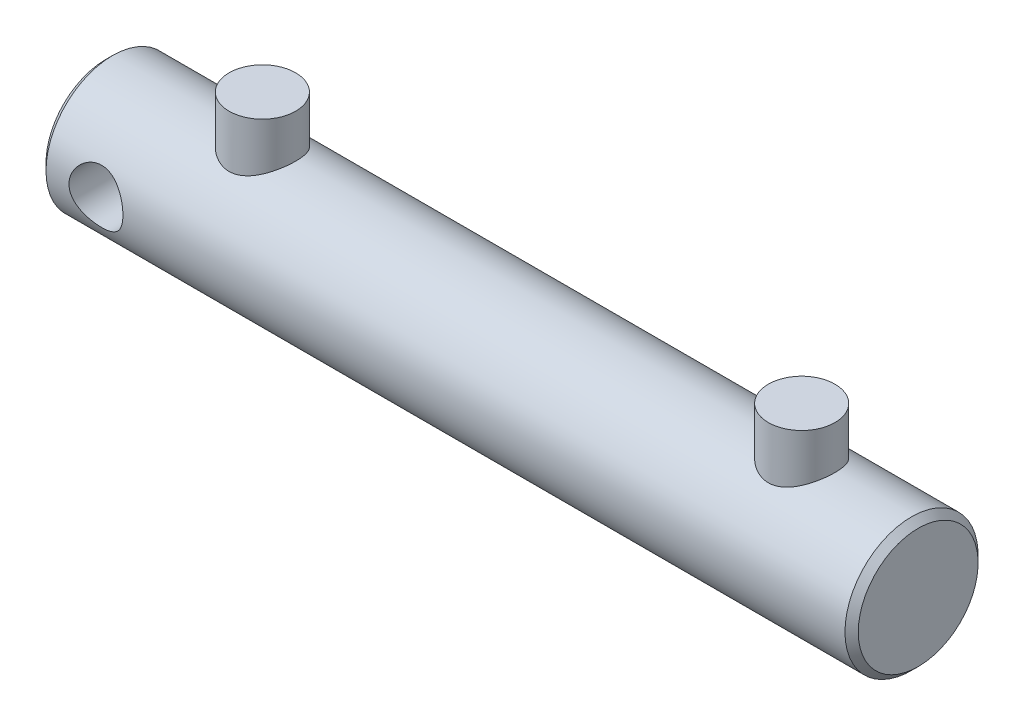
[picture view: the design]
ISO-10303-21;
HEADER;
FILE_DESCRIPTION(('STEP AP214'),'2;1');
FILE_NAME('part.step','',(''),(''),'','','');
FILE_SCHEMA(('AUTOMOTIVE_DESIGN { 1 0 10303 214 1 1 1 1 }'));
ENDSEC;
DATA;
#1=APPLICATION_CONTEXT('core data for automotive mechanical design processes');
#2=APPLICATION_PROTOCOL_DEFINITION('international standard','automotive_design',2000,#1);
#3=PRODUCT_CONTEXT('',#1,'mechanical');
#4=PRODUCT('Part','Part','',(#3));
#5=PRODUCT_RELATED_PRODUCT_CATEGORY('part','',(#4));
#6=PRODUCT_DEFINITION_FORMATION('','',#4);
#7=PRODUCT_DEFINITION_CONTEXT('part definition',#1,'design');
#8=PRODUCT_DEFINITION('design','',#6,#7);
#9=PRODUCT_DEFINITION_SHAPE('','',#8);
#10=(LENGTH_UNIT() NAMED_UNIT(*) SI_UNIT(.MILLI.,.METRE.));
#11=(NAMED_UNIT(*) PLANE_ANGLE_UNIT() SI_UNIT($,.RADIAN.));
#12=(NAMED_UNIT(*) SI_UNIT($,.STERADIAN.) SOLID_ANGLE_UNIT());
#13=UNCERTAINTY_MEASURE_WITH_UNIT(LENGTH_MEASURE(1.E-05),#10,'distance_accuracy_value','');
#14=(GEOMETRIC_REPRESENTATION_CONTEXT(3) GLOBAL_UNCERTAINTY_ASSIGNED_CONTEXT((#13)) GLOBAL_UNIT_ASSIGNED_CONTEXT((#10,
#11,#12)) REPRESENTATION_CONTEXT('',''));
#15=CARTESIAN_POINT('',(0.,0.,0.));
#16=DIRECTION('',(0.,0.,1.));
#17=DIRECTION('',(1.,0.,0.));
#18=AXIS2_PLACEMENT_3D('',#15,#16,#17);
#19=CARTESIAN_POINT('',(-122.,0.,0.));
#20=DIRECTION('',(-1.,0.,0.));
#21=DIRECTION('',(0.,0.,1.));
#22=AXIS2_PLACEMENT_3D('',#19,#20,#21);
#23=CYLINDRICAL_SURFACE('',#22,20.);
#24=CARTESIAN_POINT('',(-75.0000000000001,17.3205080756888,-10.));
#25=CARTESIAN_POINT('',(-75.2606630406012,17.3205095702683,-9.99999887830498));
#26=CARTESIAN_POINT('',(-75.5213487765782,17.3264124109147,-9.98979463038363));
#27=CARTESIAN_POINT('',(-76.0407114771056,17.3498046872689,-9.94911125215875));
#28=CARTESIAN_POINT('',(-76.2993874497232,17.3672995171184,-9.91862268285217));
#29=CARTESIAN_POINT('',(-76.8130233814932,17.4132568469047,-9.83771551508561));
#30=CARTESIAN_POINT('',(-77.0679768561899,17.4417365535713,-9.78726564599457));
#31=CARTESIAN_POINT('',(-77.5720498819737,17.5086546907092,-9.66704369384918));
#32=CARTESIAN_POINT('',(-77.821166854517,17.5470974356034,-9.59726323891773));
#33=CARTESIAN_POINT('',(-78.3104736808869,17.6323996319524,-9.43962165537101));
#34=CARTESIAN_POINT('',(-78.5507068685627,17.6792090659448,-9.35186754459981));
#35=CARTESIAN_POINT('',(-79.0225542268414,17.779982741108,-9.15882440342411));
#36=CARTESIAN_POINT('',(-79.2541652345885,17.8339495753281,-9.05352901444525));
#37=CARTESIAN_POINT('',(-79.7075453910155,17.9475017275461,-8.82628481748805));
#38=CARTESIAN_POINT('',(-79.9293168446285,18.007085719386,-8.70433993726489));
#39=CARTESIAN_POINT('',(-80.3621596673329,18.1303531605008,-8.4445816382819));
#40=CARTESIAN_POINT('',(-80.573230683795,18.1940367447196,-8.30676769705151));
#41=CARTESIAN_POINT('',(-81.000837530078,18.329363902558,-8.00400718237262));
#42=CARTESIAN_POINT('',(-81.216382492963,18.4012302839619,-7.83775940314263));
#43=CARTESIAN_POINT('',(-81.6329349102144,18.5460965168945,-7.48852658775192));
#44=CARTESIAN_POINT('',(-81.8339460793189,18.6190960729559,-7.30554585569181));
#45=CARTESIAN_POINT('',(-82.2206945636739,18.7644955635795,-6.92354675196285));
#46=CARTESIAN_POINT('',(-82.4064192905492,18.8368949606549,-6.72451542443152));
#47=CARTESIAN_POINT('',(-82.7613467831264,18.9792540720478,-6.3115450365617));
#48=CARTESIAN_POINT('',(-82.9305553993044,19.0492146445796,-6.09761130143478));
#49=CARTESIAN_POINT('',(-83.2623641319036,19.1896470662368,-5.64077435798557));
#50=CARTESIAN_POINT('',(-83.4237392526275,19.2598322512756,-5.39689043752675));
#51=CARTESIAN_POINT('',(-83.7252065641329,19.3935808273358,-4.89454568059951));
#52=CARTESIAN_POINT('',(-83.8652975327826,19.4571438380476,-4.63608400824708));
#53=CARTESIAN_POINT('',(-84.1227489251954,19.5757886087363,-4.10635184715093));
#54=CARTESIAN_POINT('',(-84.240120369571,19.6308744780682,-3.83508764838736));
#55=CARTESIAN_POINT('',(-84.4508629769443,19.7309453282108,-3.28159286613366));
#56=CARTESIAN_POINT('',(-84.5442366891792,19.775931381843,-2.99936345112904));
#57=CARTESIAN_POINT('',(-84.7000287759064,19.8516061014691,-2.44661617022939));
#58=CARTESIAN_POINT('',(-84.7641767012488,19.8830841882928,-2.17669338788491));
#59=CARTESIAN_POINT('',(-84.8699306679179,19.9352303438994,-1.6314331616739));
#60=CARTESIAN_POINT('',(-84.9115376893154,19.9558988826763,-1.35609595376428));
#61=CARTESIAN_POINT('',(-84.9716398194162,19.9858180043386,-0.802434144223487));
#62=CARTESIAN_POINT('',(-84.9901467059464,19.9950744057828,-0.52411113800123));
#63=CARTESIAN_POINT('',(-85.003828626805,20.001913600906,0.0332441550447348));
#64=CARTESIAN_POINT('',(-84.9990050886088,19.9994971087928,0.31227639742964));
#65=CARTESIAN_POINT('',(-84.9675360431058,19.9837839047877,0.844365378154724));
#66=CARTESIAN_POINT('',(-84.9428274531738,19.9714530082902,1.09756809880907));
#67=CARTESIAN_POINT('',(-84.8743173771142,19.9374335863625,1.60072224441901));
#68=CARTESIAN_POINT('',(-84.8305172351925,19.9157457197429,1.85067389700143));
#69=CARTESIAN_POINT('',(-84.7243003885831,19.8635314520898,2.34564683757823));
#70=CARTESIAN_POINT('',(-84.6618830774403,19.8330047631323,2.59066796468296));
#71=CARTESIAN_POINT('',(-84.5190690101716,19.7638249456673,3.0742307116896));
#72=CARTESIAN_POINT('',(-84.4386716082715,19.7251715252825,3.31277209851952));
#73=CARTESIAN_POINT('',(-84.2594279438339,19.6400278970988,3.78519130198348));
#74=CARTESIAN_POINT('',(-84.1603459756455,19.5934383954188,4.01896179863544));
#75=CARTESIAN_POINT('',(-83.9453098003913,19.4938328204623,4.47722728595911));
#76=CARTESIAN_POINT('',(-83.8293496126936,19.4408144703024,4.70171895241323));
#77=CARTESIAN_POINT('',(-83.4574852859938,19.2738101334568,5.35951935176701));
#78=CARTESIAN_POINT('',(-83.1774883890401,19.1518214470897,5.7774381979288));
#79=CARTESIAN_POINT('',(-82.5309599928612,18.8844067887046,6.60185513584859));
#80=CARTESIAN_POINT('',(-82.1587504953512,18.7378553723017,7.00353936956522));
#81=CARTESIAN_POINT('',(-81.5553615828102,18.5185765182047,7.55658054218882));
#82=CARTESIAN_POINT('',(-81.346548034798,18.4455210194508,7.73279224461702));
#83=CARTESIAN_POINT('',(-80.9146773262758,18.301419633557,8.06791510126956));
#84=CARTESIAN_POINT('',(-80.6916180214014,18.2303740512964,8.22682364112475));
#85=CARTESIAN_POINT('',(-80.2176662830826,18.0878347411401,8.53586780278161));
#86=CARTESIAN_POINT('',(-79.9659060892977,18.0166021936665,8.68479491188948));
#87=CARTESIAN_POINT('',(-79.448949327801,17.8810231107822,8.9606151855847));
#88=CARTESIAN_POINT('',(-79.1837588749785,17.8166734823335,9.08751826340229));
#89=CARTESIAN_POINT('',(-78.6415971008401,17.6972138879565,9.31801905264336));
#90=CARTESIAN_POINT('',(-78.3646328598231,17.6420984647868,9.42163054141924));
#91=CARTESIAN_POINT('',(-77.8007562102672,17.5432965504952,9.60435110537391));
#92=CARTESIAN_POINT('',(-77.5138451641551,17.4996085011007,9.68346352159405));
#93=CARTESIAN_POINT('',(-76.9554952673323,17.4285246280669,9.81078056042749));
#94=CARTESIAN_POINT('',(-76.6846306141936,17.400112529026,9.86093677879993));
#95=CARTESIAN_POINT('',(-76.1386742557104,17.355765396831,9.93878416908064));
#96=CARTESIAN_POINT('',(-75.8635827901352,17.3398296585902,9.96647661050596));
#97=CARTESIAN_POINT('',(-75.3117693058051,17.3211203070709,9.99895720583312));
#98=CARTESIAN_POINT('',(-75.035048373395,17.3183387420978,10.0037591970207));
#99=CARTESIAN_POINT('',(-74.4823571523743,17.3260388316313,9.99041751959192));
#100=CARTESIAN_POINT('',(-74.2063868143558,17.3365195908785,9.97227539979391));
#101=CARTESIAN_POINT('',(-73.6878300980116,17.3684286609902,9.91658048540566));
#102=CARTESIAN_POINT('',(-73.4449043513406,17.3885290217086,9.88137691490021));
#103=CARTESIAN_POINT('',(-72.9631581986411,17.4382137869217,9.79342893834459));
#104=CARTESIAN_POINT('',(-72.7243391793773,17.467801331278,9.74067872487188));
#105=CARTESIAN_POINT('',(-72.2523728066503,17.5355331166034,9.61821012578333));
#106=CARTESIAN_POINT('',(-72.0192247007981,17.5736762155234,9.54849400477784));
#107=CARTESIAN_POINT('',(-71.5597756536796,17.6574071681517,9.39275103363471));
#108=CARTESIAN_POINT('',(-71.3334774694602,17.7029979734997,9.30671771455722));
#109=CARTESIAN_POINT('',(-70.6461619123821,17.8535843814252,9.01657018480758));
#110=CARTESIAN_POINT('',(-70.1983271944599,17.9691397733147,8.78600743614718));
#111=CARTESIAN_POINT('',(-69.3451898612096,18.2156365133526,8.26280380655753));
#112=CARTESIAN_POINT('',(-68.93990925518,18.3465857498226,7.97013103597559));
#113=CARTESIAN_POINT('',(-68.3445899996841,18.5540860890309,7.46888401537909));
#114=CARTESIAN_POINT('',(-68.1378065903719,18.6294365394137,7.27935116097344));
#115=CARTESIAN_POINT('',(-67.7407576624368,18.7793184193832,6.8834540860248));
#116=CARTESIAN_POINT('',(-67.5504872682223,18.8538500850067,6.67709486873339));
#117=CARTESIAN_POINT('',(-67.1874055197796,19.0002370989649,6.24838707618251));
#118=CARTESIAN_POINT('',(-67.0146073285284,19.0720904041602,6.02602665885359));
#119=CARTESIAN_POINT('',(-66.687849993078,19.2111944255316,5.56664786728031));
#120=CARTESIAN_POINT('',(-66.533882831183,19.2784470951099,5.32963579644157));
#121=CARTESIAN_POINT('',(-66.2420643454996,19.4083463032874,4.83560208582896));
#122=CARTESIAN_POINT('',(-66.1047543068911,19.4708214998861,4.57821478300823));
#123=CARTESIAN_POINT('',(-65.8525290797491,19.5873354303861,4.05082787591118));
#124=CARTESIAN_POINT('',(-65.7376146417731,19.6413738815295,3.78082784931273));
#125=CARTESIAN_POINT('',(-65.5315676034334,19.7393769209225,3.23033940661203));
#126=CARTESIAN_POINT('',(-65.4404180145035,19.7833487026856,2.94985864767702));
#127=CARTESIAN_POINT('',(-65.2829809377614,19.8599022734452,2.38049331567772));
#128=CARTESIAN_POINT('',(-65.2166905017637,19.8924854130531,2.09160974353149));
#129=CARTESIAN_POINT('',(-65.1148104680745,19.942798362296,1.53480500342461));
#130=CARTESIAN_POINT('',(-65.0769613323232,19.9616170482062,1.26739371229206));
#131=CARTESIAN_POINT('',(-65.0230133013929,19.9884894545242,0.729851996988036));
#132=CARTESIAN_POINT('',(-65.0069130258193,19.9965438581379,0.459721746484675));
#133=CARTESIAN_POINT('',(-64.996673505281,20.0016629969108,-0.0809759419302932));
#134=CARTESIAN_POINT('',(-65.0025277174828,19.998731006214,-0.351543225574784));
#135=CARTESIAN_POINT('',(-65.0361056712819,19.9819662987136,-0.890971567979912));
#136=CARTESIAN_POINT('',(-65.0638288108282,19.9681338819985,-1.15983267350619));
#137=CARTESIAN_POINT('',(-65.1382400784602,19.9312153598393,-1.67605139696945));
#138=CARTESIAN_POINT('',(-65.18355535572,19.9088004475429,-1.9236568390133));
#139=CARTESIAN_POINT('',(-65.292457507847,19.8553300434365,-2.41384547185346));
#140=CARTESIAN_POINT('',(-65.3560433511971,19.8242750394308,-2.65642894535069));
#141=CARTESIAN_POINT('',(-65.5008477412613,19.7542370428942,-3.13506320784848));
#142=CARTESIAN_POINT('',(-65.5820646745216,19.7152547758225,-3.3711145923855));
#143=CARTESIAN_POINT('',(-65.7614308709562,19.6302044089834,-3.83546861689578));
#144=CARTESIAN_POINT('',(-65.8595866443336,19.5841335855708,-4.06376823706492));
#145=CARTESIAN_POINT('',(-66.0765183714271,19.483810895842,-4.52085803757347));
#146=CARTESIAN_POINT('',(-66.1959918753,19.4292950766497,-4.74925902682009));
#147=CARTESIAN_POINT('',(-66.4515659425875,19.3148302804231,-5.19522438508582));
#148=CARTESIAN_POINT('',(-66.587672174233,19.2548794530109,-5.4127850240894));
#149=CARTESIAN_POINT('',(-66.8755967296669,19.1308402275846,-5.83606045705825));
#150=CARTESIAN_POINT('',(-67.0274181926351,19.0667510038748,-6.0417728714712));
#151=CARTESIAN_POINT('',(-67.3458750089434,18.9358010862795,-6.44045588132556));
#152=CARTESIAN_POINT('',(-67.5125111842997,18.8689402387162,-6.63342576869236));
#153=CARTESIAN_POINT('',(-67.8770952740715,18.7271146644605,-7.02443076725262));
#154=CARTESIAN_POINT('',(-68.0765084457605,18.6520069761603,-7.22105023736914));
#155=CARTESIAN_POINT('',(-68.4911102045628,18.5021161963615,-7.59688252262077));
#156=CARTESIAN_POINT('',(-68.7062943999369,18.4273330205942,-7.77610015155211));
#157=CARTESIAN_POINT('',(-69.1516671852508,18.2800108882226,-8.1163793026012));
#158=CARTESIAN_POINT('',(-69.3818705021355,18.2074742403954,-8.27742256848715));
#159=CARTESIAN_POINT('',(-69.8560212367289,18.0668000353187,-8.58012843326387));
#160=CARTESIAN_POINT('',(-70.0999705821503,17.9986630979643,-8.72178830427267));
#161=CARTESIAN_POINT('',(-70.6083744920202,17.8668466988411,-8.98880823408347));
#162=CARTESIAN_POINT('',(-70.8732353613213,17.8033795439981,-9.11350193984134));
#163=CARTESIAN_POINT('',(-71.414528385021,17.6857538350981,-9.3397203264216));
#164=CARTESIAN_POINT('',(-71.6909544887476,17.6315904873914,-9.44125694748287));
#165=CARTESIAN_POINT('',(-72.2528111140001,17.5348420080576,-9.61975104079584));
#166=CARTESIAN_POINT('',(-72.5382163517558,17.4922271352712,-9.69677174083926));
#167=CARTESIAN_POINT('',(-73.1161855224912,17.420295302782,-9.82541504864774));
#168=CARTESIAN_POINT('',(-73.4087442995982,17.3909690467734,-9.8770554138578));
#169=CARTESIAN_POINT('',(-73.9179955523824,17.3529508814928,-9.94364603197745));
#170=CARTESIAN_POINT('',(-74.1336483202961,17.340814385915,-9.96475859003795));
#171=CARTESIAN_POINT('',(-74.5661954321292,17.3245920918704,-9.99293651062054));
#172=CARTESIAN_POINT('',(-74.7830898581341,17.3205068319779,-10.0000009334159));
#173=CARTESIAN_POINT('',(-75.0000000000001,17.3205080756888,-10.));
#174=B_SPLINE_CURVE_WITH_KNOTS('',3,(#24,#25,#26,#27,#28,#29,#30,#31,#32,#33,#34,#35,#36,#37,
#38,#39,#40,#41,#42,#43,#44,#45,#46,#47,#48,#49,#50,#51,#52,#53,#54,#55,#56,#57,#58,#59,#60,#61,
#62,#63,#64,#65,#66,#67,#68,#69,#70,#71,#72,#73,#74,#75,#76,#77,#78,#79,#80,#81,#82,#83,#84,#85,
#86,#87,#88,#89,#90,#91,#92,#93,#94,#95,#96,#97,#98,#99,#100,#101,#102,#103,#104,#105,#106,#107,
#108,#109,#110,#111,#112,#113,#114,#115,#116,#117,#118,#119,#120,#121,#122,#123,#124,#125,#126,
#127,#128,#129,#130,#131,#132,#133,#134,#135,#136,#137,#138,#139,#140,#141,#142,#143,#144,#145,
#146,#147,#148,#149,#150,#151,#152,#153,#154,#155,#156,#157,#158,#159,#160,#161,#162,#163,#164,
#165,#166,#167,#168,#169,#170,#171,#172,#173),.UNSPECIFIED.,.T.,.F.,(4,2,2,2,2,2,2,2,2,2,2,2,2,
2,2,2,2,2,2,2,2,2,2,2,2,2,2,2,2,2,2,2,2,2,2,2,2,2,2,2,2,2,2,2,2,2,2,2,2,2,2,2,2,2,2,2,2,2,2,2,2,
2,2,2,2,2,2,2,2,2,2,2,2,2,4),(0.,0.781764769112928,1.56389357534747,2.34725251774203,
3.13095125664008,3.91011273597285,4.68955727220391,5.46881824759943,6.24810488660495,
7.09181817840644,7.93531505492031,8.7794997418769,9.62338430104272,10.5244589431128,
11.4255853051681,12.3262734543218,13.2268658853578,14.0633930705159,14.8998838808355,
15.735948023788,16.571961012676,17.3351709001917,18.0983270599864,18.8615080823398,
19.6247165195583,20.3982891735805,21.1721366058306,22.7189130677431,24.4119022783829,
25.2596540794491,26.1075337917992,27.0095657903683,27.9111907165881,28.8122809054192,
29.7132481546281,30.5428616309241,31.3724282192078,32.2014932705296,33.0305023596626,
33.7685142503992,34.5067706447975,35.2449285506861,35.9833797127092,37.5272041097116,
39.0718230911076,39.9423348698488,40.8125887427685,41.6834934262,42.5540260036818,
43.4478458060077,44.3416955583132,45.2349045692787,46.1280076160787,46.9391312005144,
47.7502033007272,48.5610337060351,49.371841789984,50.1291222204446,50.8863599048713,
51.6435283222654,52.4009883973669,53.190547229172,53.980375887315,54.7703626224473,
55.5603932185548,56.4292490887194,57.297863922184,58.1673436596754,59.0369456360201,
59.934364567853,60.8313197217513,61.7259424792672,62.6199384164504,63.27043863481,
63.9209823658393),.UNSPECIFIED.);
#175=CARTESIAN_POINT('',(-75.0000000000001,17.3205080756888,-10.));
#176=VERTEX_POINT('',#175);
#177=EDGE_CURVE('E38',#176,#176,#174,.T.);
#178=ORIENTED_EDGE('',*,*,#177,.F.);
#179=EDGE_LOOP('',(#178));
#180=FACE_BOUND('',#179,.T.);
#181=CARTESIAN_POINT('',(-96.9,0.,-20.));
#182=CARTESIAN_POINT('',(-96.900001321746,0.217553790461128,-19.9999989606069));
#183=CARTESIAN_POINT('',(-96.9087767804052,0.435188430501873,-19.9964404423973));
#184=CARTESIAN_POINT('',(-96.9437988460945,0.868915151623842,-19.9822953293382));
#185=CARTESIAN_POINT('',(-96.9700569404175,1.08500612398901,-19.9717041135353));
#186=CARTESIAN_POINT('',(-97.0398578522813,1.51445060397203,-19.9437418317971));
#187=CARTESIAN_POINT('',(-97.0834401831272,1.72779669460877,-19.9263552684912));
#188=CARTESIAN_POINT('',(-97.1874521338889,2.14972461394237,-19.8852614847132));
#189=CARTESIAN_POINT('',(-97.2478829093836,2.35830611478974,-19.8615538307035));
#190=CARTESIAN_POINT('',(-97.3847842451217,2.76859175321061,-19.8085220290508));
#191=CARTESIAN_POINT('',(-97.4611994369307,2.97031690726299,-19.7792172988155));
#192=CARTESIAN_POINT('',(-97.6295344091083,3.36638434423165,-19.7156711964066));
#193=CARTESIAN_POINT('',(-97.7214547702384,3.56072635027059,-19.6814296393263));
#194=CARTESIAN_POINT('',(-97.9200165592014,3.94078379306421,-19.6088661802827));
#195=CARTESIAN_POINT('',(-98.0266492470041,4.126504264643,-19.5705467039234));
#196=CARTESIAN_POINT('',(-98.2539611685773,4.48850295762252,-19.4907084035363));
#197=CARTESIAN_POINT('',(-98.3746454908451,4.66477772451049,-19.4491884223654));
#198=CARTESIAN_POINT('',(-98.6348215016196,5.01438229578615,-19.3620718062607));
#199=CARTESIAN_POINT('',(-98.7749041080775,5.18724787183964,-19.3163763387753));
#200=CARTESIAN_POINT('',(-99.0686198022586,5.52069726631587,-19.2237314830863));
#201=CARTESIAN_POINT('',(-99.2222533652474,5.68128065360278,-19.1767820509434));
#202=CARTESIAN_POINT('',(-99.5422842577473,5.9893827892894,-19.0827999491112));
#203=CARTESIAN_POINT('',(-99.7086897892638,6.1368930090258,-19.0357672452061));
#204=CARTESIAN_POINT('',(-100.053204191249,6.41783459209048,-18.9428953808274));
#205=CARTESIAN_POINT('',(-100.231309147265,6.55127062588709,-18.8970558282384));
#206=CARTESIAN_POINT('',(-100.606840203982,6.80914100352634,-18.8057217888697));
#207=CARTESIAN_POINT('',(-100.804779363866,6.93287030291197,-18.760342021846));
#208=CARTESIAN_POINT('',(-101.21120099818,7.16306636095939,-18.6736608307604));
#209=CARTESIAN_POINT('',(-101.419679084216,7.26954022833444,-18.6323577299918));
#210=CARTESIAN_POINT('',(-101.845884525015,7.46434474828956,-18.5551755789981));
#211=CARTESIAN_POINT('',(-102.063610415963,7.55267825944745,-18.5192956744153));
#212=CARTESIAN_POINT('',(-102.506807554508,7.71033713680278,-18.4542132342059));
#213=CARTESIAN_POINT('',(-102.732278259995,7.77966383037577,-18.4250102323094));
#214=CARTESIAN_POINT('',(-103.178677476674,7.89578945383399,-18.3755355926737));
#215=CARTESIAN_POINT('',(-103.399335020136,7.94348076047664,-18.3549138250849));
#216=CARTESIAN_POINT('',(-103.844442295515,8.02032945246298,-18.3214649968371));
#217=CARTESIAN_POINT('',(-104.06889191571,8.04948738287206,-18.3086377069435));
#218=CARTESIAN_POINT('',(-104.519666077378,8.08890880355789,-18.2912553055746));
#219=CARTESIAN_POINT('',(-104.745989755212,8.09918055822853,-18.2866965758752));
#220=CARTESIAN_POINT('',(-105.198709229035,8.10072505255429,-18.2860126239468));
#221=CARTESIAN_POINT('',(-105.425105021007,8.09199871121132,-18.2898869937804));
#222=CARTESIAN_POINT('',(-105.859830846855,8.05697039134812,-18.3053422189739));
#223=CARTESIAN_POINT('',(-106.068288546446,8.03197836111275,-18.3163484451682));
#224=CARTESIAN_POINT('',(-106.482250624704,7.96598244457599,-18.3451470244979));
#225=CARTESIAN_POINT('',(-106.687753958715,7.92497303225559,-18.362941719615));
#226=CARTESIAN_POINT('',(-107.094312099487,7.82735937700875,-18.404761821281));
#227=CARTESIAN_POINT('',(-107.29536798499,7.77075896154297,-18.4287856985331));
#228=CARTESIAN_POINT('',(-107.691918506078,7.64244879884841,-18.4823647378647));
#229=CARTESIAN_POINT('',(-107.887410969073,7.57073323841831,-18.5119220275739));
#230=CARTESIAN_POINT('',(-108.275541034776,7.41119054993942,-18.5763775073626));
#231=CARTESIAN_POINT('',(-108.468040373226,7.32306621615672,-18.6113718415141));
#232=CARTESIAN_POINT('',(-108.845021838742,7.13235218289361,-18.6852885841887));
#233=CARTESIAN_POINT('',(-109.029501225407,7.02975758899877,-18.7242123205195));
#234=CARTESIAN_POINT('',(-109.389462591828,6.81080050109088,-18.8049623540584));
#235=CARTESIAN_POINT('',(-109.564943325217,6.69443610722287,-18.8467890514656));
#236=CARTESIAN_POINT('',(-109.90603190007,6.4486467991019,-18.932297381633));
#237=CARTESIAN_POINT('',(-110.071639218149,6.31922119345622,-18.975979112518));
#238=CARTESIAN_POINT('',(-110.404955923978,6.03720358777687,-19.0676654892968));
#239=CARTESIAN_POINT('',(-110.571781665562,5.88358742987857,-19.1157372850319));
#240=CARTESIAN_POINT('',(-110.891974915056,5.56290919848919,-19.2115077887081));
#241=CARTESIAN_POINT('',(-111.045346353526,5.39585107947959,-19.2592066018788));
#242=CARTESIAN_POINT('',(-111.337835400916,5.0490907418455,-19.3530089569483));
#243=CARTESIAN_POINT('',(-111.476944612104,4.86938117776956,-19.3991115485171));
#244=CARTESIAN_POINT('',(-111.739815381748,4.49850306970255,-19.4884538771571));
#245=CARTESIAN_POINT('',(-111.86358307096,4.30733914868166,-19.5316947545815));
#246=CARTESIAN_POINT('',(-112.097369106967,3.91043655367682,-19.6150570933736));
#247=CARTESIAN_POINT('',(-112.207039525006,3.70447453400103,-19.6550927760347));
#248=CARTESIAN_POINT('',(-112.408471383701,3.28314601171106,-19.729842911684));
#249=CARTESIAN_POINT('',(-112.500240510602,3.06778359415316,-19.7645596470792));
#250=CARTESIAN_POINT('',(-112.665018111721,2.62913934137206,-19.8276753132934));
#251=CARTESIAN_POINT('',(-112.738030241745,2.40585905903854,-19.8560754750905));
#252=CARTESIAN_POINT('',(-112.864528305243,1.95305901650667,-19.9057131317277));
#253=CARTESIAN_POINT('',(-112.918015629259,1.7235397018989,-19.926951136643));
#254=CARTESIAN_POINT('',(-113.002224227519,1.27415358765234,-19.9605660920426));
#255=CARTESIAN_POINT('',(-113.034125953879,1.05454166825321,-19.9734009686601));
#256=CARTESIAN_POINT('',(-113.079807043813,0.613140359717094,-19.9918193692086));
#257=CARTESIAN_POINT('',(-113.093587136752,0.391351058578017,-19.9974031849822));
#258=CARTESIAN_POINT('',(-113.102871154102,-0.0526198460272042,-20.0011625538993));
#259=CARTESIAN_POINT('',(-113.098379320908,-0.274801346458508,-19.9993398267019));
#260=CARTESIAN_POINT('',(-113.071179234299,-0.71785978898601,-19.9883410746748));
#261=CARTESIAN_POINT('',(-113.048471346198,-0.938736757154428,-19.9791651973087));
#262=CARTESIAN_POINT('',(-112.986569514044,-1.36724903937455,-19.954311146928));
#263=CARTESIAN_POINT('',(-112.948192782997,-1.57502190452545,-19.9389557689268));
#264=CARTESIAN_POINT('',(-112.855464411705,-1.98649733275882,-19.9021734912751));
#265=CARTESIAN_POINT('',(-112.801107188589,-2.19019844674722,-19.8807444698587));
#266=CARTESIAN_POINT('',(-112.676934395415,-2.59208434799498,-19.8323487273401));
#267=CARTESIAN_POINT('',(-112.607123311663,-2.79027071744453,-19.8053836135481));
#268=CARTESIAN_POINT('',(-112.452592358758,-3.18006963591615,-19.7465447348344));
#269=CARTESIAN_POINT('',(-112.367866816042,-3.37167964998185,-19.7146691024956));
#270=CARTESIAN_POINT('',(-112.181383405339,-3.75288057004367,-19.6457256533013));
#271=CARTESIAN_POINT('',(-112.079186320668,-3.94223332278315,-19.6085295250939));
#272=CARTESIAN_POINT('',(-111.860392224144,-4.31174450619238,-19.5306049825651));
#273=CARTESIAN_POINT('',(-111.743790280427,-4.49189975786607,-19.4898753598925));
#274=CARTESIAN_POINT('',(-111.496967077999,-4.84203534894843,-19.4058526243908));
#275=CARTESIAN_POINT('',(-111.366743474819,-5.01201392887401,-19.3625590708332));
#276=CARTESIAN_POINT('',(-111.093473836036,-5.34090761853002,-19.2744311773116));
#277=CARTESIAN_POINT('',(-110.95042722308,-5.49982222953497,-19.2295967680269));
#278=CARTESIAN_POINT('',(-110.642171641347,-5.81617801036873,-19.1363810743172));
#279=CARTESIAN_POINT('',(-110.476117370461,-5.97278662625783,-19.0879656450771));
#280=CARTESIAN_POINT('',(-110.131317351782,-6.27149075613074,-18.9919197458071));
#281=CARTESIAN_POINT('',(-109.952575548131,-6.41359074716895,-18.9442890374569));
#282=CARTESIAN_POINT('',(-109.583258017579,-6.68251089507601,-18.8511091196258));
#283=CARTESIAN_POINT('',(-109.392675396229,-6.80932202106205,-18.8055611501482));
#284=CARTESIAN_POINT('',(-109.000949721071,-7.04661740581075,-18.7179373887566));
#285=CARTESIAN_POINT('',(-108.79981115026,-7.15710852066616,-18.6758601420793));
#286=CARTESIAN_POINT('',(-108.385735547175,-7.36211754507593,-18.5960069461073));
#287=CARTESIAN_POINT('',(-108.17268924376,-7.45643666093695,-18.5582861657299));
#288=CARTESIAN_POINT('',(-107.738475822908,-7.62660439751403,-18.4890062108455));
#289=CARTESIAN_POINT('',(-107.517312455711,-7.70246142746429,-18.4574442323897));
#290=CARTESIAN_POINT('',(-107.068484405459,-7.834927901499,-18.4016053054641));
#291=CARTESIAN_POINT('',(-106.840822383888,-7.89154510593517,-18.3773254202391));
#292=CARTESIAN_POINT('',(-106.380747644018,-7.98489928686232,-18.3369567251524));
#293=CARTESIAN_POINT('',(-106.148335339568,-8.02163798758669,-18.3208672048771));
#294=CARTESIAN_POINT('',(-105.697962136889,-8.07281706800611,-18.2983698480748));
#295=CARTESIAN_POINT('',(-105.480195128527,-8.08869834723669,-18.2913371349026));
#296=CARTESIAN_POINT('',(-105.043982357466,-8.10281912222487,-18.2850864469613));
#297=CARTESIAN_POINT('',(-104.825536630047,-8.10105952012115,-18.2858680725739));
#298=CARTESIAN_POINT('',(-104.389698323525,-8.07992140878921,-18.2952179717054));
#299=CARTESIAN_POINT('',(-104.172305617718,-8.06054507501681,-18.3037852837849));
#300=CARTESIAN_POINT('',(-103.740212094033,-8.00439867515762,-18.3284079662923));
#301=CARTESIAN_POINT('',(-103.525511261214,-7.9676287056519,-18.3444632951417));
#302=CARTESIAN_POINT('',(-103.109281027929,-7.87899425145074,-18.3827003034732));
#303=CARTESIAN_POINT('',(-102.907576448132,-7.82782592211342,-18.4045974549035));
#304=CARTESIAN_POINT('',(-102.509277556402,-7.71034555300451,-18.4541223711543));
#305=CARTESIAN_POINT('',(-102.312685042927,-7.644028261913,-18.4817521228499));
#306=CARTESIAN_POINT('',(-101.925853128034,-7.4968289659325,-18.5419489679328));
#307=CARTESIAN_POINT('',(-101.735612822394,-7.41594904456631,-18.5745153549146));
#308=CARTESIAN_POINT('',(-101.362404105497,-7.24019743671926,-18.6437243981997));
#309=CARTESIAN_POINT('',(-101.179438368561,-7.14532066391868,-18.6803685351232));
#310=CARTESIAN_POINT('',(-100.811381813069,-6.93634048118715,-18.7590072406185));
#311=CARTESIAN_POINT('',(-100.626782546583,-6.82144138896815,-18.8011888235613));
#312=CARTESIAN_POINT('',(-100.26777997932,-6.57747679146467,-18.8879208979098));
#313=CARTESIAN_POINT('',(-100.093377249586,-6.44841049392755,-18.9324715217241));
#314=CARTESIAN_POINT('',(-99.7555968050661,-6.17682899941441,-19.0228091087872));
#315=CARTESIAN_POINT('',(-99.5922237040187,-6.03430823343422,-19.0685965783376));
#316=CARTESIAN_POINT('',(-99.2774813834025,-5.73669576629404,-19.1602337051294));
#317=CARTESIAN_POINT('',(-99.1261085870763,-5.58160783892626,-19.2060833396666));
#318=CARTESIAN_POINT('',(-98.8263194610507,-5.24873029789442,-19.2998110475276));
#319=CARTESIAN_POINT('',(-98.678795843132,-5.07011468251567,-19.3476165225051));
#320=CARTESIAN_POINT('',(-98.3993545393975,-4.70054560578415,-19.4407090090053));
#321=CARTESIAN_POINT('',(-98.2674316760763,-4.50959627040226,-19.4859968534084));
#322=CARTESIAN_POINT('',(-98.0200294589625,-4.11631109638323,-19.5728526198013));
#323=CARTESIAN_POINT('',(-97.9045622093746,-3.91396702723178,-19.6144177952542));
#324=CARTESIAN_POINT('',(-97.6911665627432,-3.49932983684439,-19.6926175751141));
#325=CARTESIAN_POINT('',(-97.5932367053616,-3.2870375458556,-19.7292525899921));
#326=CARTESIAN_POINT('',(-97.4174184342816,-2.85784311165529,-19.7959350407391));
#327=CARTESIAN_POINT('',(-97.3392019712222,-2.64109201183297,-19.8260888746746));
#328=CARTESIAN_POINT('',(-97.2013523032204,-2.20096724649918,-19.8797603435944));
#329=CARTESIAN_POINT('',(-97.1417172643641,-1.97759423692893,-19.9032786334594));
#330=CARTESIAN_POINT('',(-97.0418076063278,-1.52656255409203,-19.9429368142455));
#331=CARTESIAN_POINT('',(-97.0014810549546,-1.29891710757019,-19.959096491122));
#332=CARTESIAN_POINT('',(-96.94043734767,-0.840712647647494,-19.9836373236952));
#333=CARTESIAN_POINT('',(-96.9197054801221,-0.610155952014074,-19.9920243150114));
#334=CARTESIAN_POINT('',(-96.9059195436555,-0.316014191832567,-19.9976033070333));
#335=CARTESIAN_POINT('',(-96.9037002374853,-0.252837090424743,-19.998501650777));
#336=CARTESIAN_POINT('',(-96.9007402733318,-0.126442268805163,-19.9997001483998));
#337=CARTESIAN_POINT('',(-96.8999996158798,-0.0632245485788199,-20.0000003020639));
#338=CARTESIAN_POINT('',(-96.9,0.,-20.));
#339=B_SPLINE_CURVE_WITH_KNOTS('',3,(#181,#182,#183,#184,#185,#186,#187,#188,#189,#190,#191,
#192,#193,#194,#195,#196,#197,#198,#199,#200,#201,#202,#203,#204,#205,#206,#207,#208,#209,#210,
#211,#212,#213,#214,#215,#216,#217,#218,#219,#220,#221,#222,#223,#224,#225,#226,#227,#228,#229,
#230,#231,#232,#233,#234,#235,#236,#237,#238,#239,#240,#241,#242,#243,#244,#245,#246,#247,#248,
#249,#250,#251,#252,#253,#254,#255,#256,#257,#258,#259,#260,#261,#262,#263,#264,#265,#266,#267,
#268,#269,#270,#271,#272,#273,#274,#275,#276,#277,#278,#279,#280,#281,#282,#283,#284,#285,#286,
#287,#288,#289,#290,#291,#292,#293,#294,#295,#296,#297,#298,#299,#300,#301,#302,#303,#304,#305,
#306,#307,#308,#309,#310,#311,#312,#313,#314,#315,#316,#317,#318,#319,#320,#321,#322,#323,#324,
#325,#326,#327,#328,#329,#330,#331,#332,#333,#334,#335,#336,#337,#338),.UNSPECIFIED.,.T.,.F.,(4,
2,2,2,2,2,2,2,2,2,2,2,2,2,2,2,2,2,2,2,2,2,2,2,2,2,2,2,2,2,2,2,2,2,2,2,2,2,2,2,2,2,2,2,2,2,2,2,2,
2,2,2,2,2,2,2,2,2,2,2,2,2,2,2,2,2,2,2,2,2,2,2,2,2,2,2,2,2,4),(0.,0.652596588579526,
1.30562240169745,1.9601462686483,2.61471503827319,3.26705291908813,3.91941523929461,
4.57139167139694,5.22360494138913,5.90428093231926,6.58498080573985,7.26612153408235,
7.94703551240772,8.65954656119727,9.37176332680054,10.0838677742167,10.795922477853,
11.4750993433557,12.1542562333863,12.8331158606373,13.5119426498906,14.1419204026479,
14.7721156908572,15.402156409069,16.0324398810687,16.6755035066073,17.3187851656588,
17.9621556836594,18.6055602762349,19.3002237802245,19.9946836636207,20.6895501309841,
21.3841380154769,22.0934810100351,22.8025187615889,23.5114182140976,24.2202671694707,
24.8862793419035,25.552264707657,26.2180954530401,26.8839128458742,27.5187156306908,
28.1537404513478,28.788581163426,29.4236638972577,30.0780389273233,30.7326386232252,
31.3873511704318,32.0420932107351,32.7412878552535,33.4402660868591,34.1396551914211,
34.8387496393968,35.5459021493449,36.2527319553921,36.9592763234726,37.6657593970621,
38.3202973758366,38.9748018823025,39.6292255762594,40.283645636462,40.9106764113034,
41.5379248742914,42.1650836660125,42.7924709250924,43.4562239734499,44.1200141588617,
44.7840803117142,45.4479477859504,46.1567243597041,46.8652650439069,47.5743242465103,
48.2833243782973,48.9796040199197,49.67581491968,50.37014261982,51.0639486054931,
51.2536033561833,51.4432581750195),.UNSPECIFIED.);
#340=CARTESIAN_POINT('',(-96.9,0.,-20.));
#341=VERTEX_POINT('',#340);
#342=EDGE_CURVE('E42',#341,#341,#339,.T.);
#343=ORIENTED_EDGE('',*,*,#342,.T.);
#344=EDGE_LOOP('',(#343));
#345=FACE_BOUND('',#344,.T.);
#346=CARTESIAN_POINT('',(-96.9,0.,20.));
#347=CARTESIAN_POINT('',(-96.900001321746,-0.217553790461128,19.9999989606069));
#348=CARTESIAN_POINT('',(-96.9087767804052,-0.435188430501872,19.9964404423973));
#349=CARTESIAN_POINT('',(-96.9437988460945,-0.86891515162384,19.9822953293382));
#350=CARTESIAN_POINT('',(-96.9700569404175,-1.08500612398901,19.9717041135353));
#351=CARTESIAN_POINT('',(-97.0398578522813,-1.51445060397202,19.9437418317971));
#352=CARTESIAN_POINT('',(-97.0834401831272,-1.72779669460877,19.9263552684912));
#353=CARTESIAN_POINT('',(-97.1874521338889,-2.14972461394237,19.8852614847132));
#354=CARTESIAN_POINT('',(-97.2478829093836,-2.35830611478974,19.8615538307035));
#355=CARTESIAN_POINT('',(-97.3847842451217,-2.7685917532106,19.8085220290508));
#356=CARTESIAN_POINT('',(-97.4611994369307,-2.97031690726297,19.7792172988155));
#357=CARTESIAN_POINT('',(-97.6295344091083,-3.36638434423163,19.7156711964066));
#358=CARTESIAN_POINT('',(-97.7214547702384,-3.56072635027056,19.6814296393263));
#359=CARTESIAN_POINT('',(-97.9200165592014,-3.94078379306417,19.6088661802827));
#360=CARTESIAN_POINT('',(-98.0266492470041,-4.12650426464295,19.5705467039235));
#361=CARTESIAN_POINT('',(-98.2539611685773,-4.48850295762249,19.4907084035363));
#362=CARTESIAN_POINT('',(-98.374645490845,-4.66477772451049,19.4491884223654));
#363=CARTESIAN_POINT('',(-98.6348215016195,-5.01438229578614,19.3620718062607));
#364=CARTESIAN_POINT('',(-98.7749041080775,-5.18724787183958,19.3163763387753));
#365=CARTESIAN_POINT('',(-99.0686198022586,-5.52069726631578,19.2237314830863));
#366=CARTESIAN_POINT('',(-99.2222533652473,-5.68128065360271,19.1767820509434));
#367=CARTESIAN_POINT('',(-99.5422842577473,-5.98938278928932,19.0827999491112));
#368=CARTESIAN_POINT('',(-99.7086897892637,-6.1368930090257,19.0357672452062));
#369=CARTESIAN_POINT('',(-100.053204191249,-6.41783459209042,18.9428953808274));
#370=CARTESIAN_POINT('',(-100.231309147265,-6.55127062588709,18.8970558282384));
#371=CARTESIAN_POINT('',(-100.606840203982,-6.80914100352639,18.8057217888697));
#372=CARTESIAN_POINT('',(-100.804779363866,-6.93287030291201,18.760342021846));
#373=CARTESIAN_POINT('',(-101.21120099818,-7.16306636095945,18.6736608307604));
#374=CARTESIAN_POINT('',(-101.419679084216,-7.26954022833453,18.6323577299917));
#375=CARTESIAN_POINT('',(-101.845884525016,-7.46434474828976,18.555175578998));
#376=CARTESIAN_POINT('',(-102.063610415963,-7.55267825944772,18.5192956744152));
#377=CARTESIAN_POINT('',(-102.506807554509,-7.71033713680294,18.4542132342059));
#378=CARTESIAN_POINT('',(-102.732278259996,-7.77966383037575,18.4250102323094));
#379=CARTESIAN_POINT('',(-103.178677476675,-7.89578945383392,18.3755355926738));
#380=CARTESIAN_POINT('',(-103.399335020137,-7.94348076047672,18.3549138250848));
#381=CARTESIAN_POINT('',(-103.844442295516,-8.02032945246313,18.321464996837));
#382=CARTESIAN_POINT('',(-104.068891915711,-8.04948738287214,18.3086377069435));
#383=CARTESIAN_POINT('',(-104.519666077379,-8.08890880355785,18.2912553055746));
#384=CARTESIAN_POINT('',(-104.745989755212,-8.09918055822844,18.2866965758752));
#385=CARTESIAN_POINT('',(-105.198709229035,-8.10072505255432,18.2860126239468));
#386=CARTESIAN_POINT('',(-105.425105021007,-8.09199871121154,18.2898869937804));
#387=CARTESIAN_POINT('',(-105.859830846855,-8.05697039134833,18.3053422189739));
#388=CARTESIAN_POINT('',(-106.068288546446,-8.03197836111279,18.3163484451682));
#389=CARTESIAN_POINT('',(-106.482250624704,-7.96598244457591,18.3451470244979));
#390=CARTESIAN_POINT('',(-106.687753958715,-7.92497303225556,18.362941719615));
#391=CARTESIAN_POINT('',(-107.094312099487,-7.82735937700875,18.4047618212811));
#392=CARTESIAN_POINT('',(-107.29536798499,-7.77075896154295,18.4287856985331));
#393=CARTESIAN_POINT('',(-107.691918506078,-7.64244879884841,18.4823647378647));
#394=CARTESIAN_POINT('',(-107.887410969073,-7.57073323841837,18.5119220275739));
#395=CARTESIAN_POINT('',(-108.275541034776,-7.41119054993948,18.5763775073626));
#396=CARTESIAN_POINT('',(-108.468040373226,-7.32306621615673,18.6113718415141));
#397=CARTESIAN_POINT('',(-108.845021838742,-7.13235218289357,18.6852885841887));
#398=CARTESIAN_POINT('',(-109.029501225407,-7.02975758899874,18.7242123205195));
#399=CARTESIAN_POINT('',(-109.389462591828,-6.81080050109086,18.8049623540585));
#400=CARTESIAN_POINT('',(-109.564943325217,-6.69443610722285,18.8467890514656));
#401=CARTESIAN_POINT('',(-109.90603190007,-6.44864679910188,18.932297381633));
#402=CARTESIAN_POINT('',(-110.071639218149,-6.31922119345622,18.975979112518));
#403=CARTESIAN_POINT('',(-110.404955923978,-6.03720358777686,19.0676654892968));
#404=CARTESIAN_POINT('',(-110.571781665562,-5.88358742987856,19.1157372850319));
#405=CARTESIAN_POINT('',(-110.891974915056,-5.56290919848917,19.2115077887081));
#406=CARTESIAN_POINT('',(-111.045346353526,-5.39585107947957,19.2592066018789));
#407=CARTESIAN_POINT('',(-111.337835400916,-5.04909074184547,19.3530089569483));
#408=CARTESIAN_POINT('',(-111.476944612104,-4.86938117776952,19.3991115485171));
#409=CARTESIAN_POINT('',(-111.739815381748,-4.49850306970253,19.4884538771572));
#410=CARTESIAN_POINT('',(-111.86358307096,-4.30733914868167,19.5316947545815));
#411=CARTESIAN_POINT('',(-112.097369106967,-3.91043655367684,19.6150570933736));
#412=CARTESIAN_POINT('',(-112.207039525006,-3.70447453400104,19.6550927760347));
#413=CARTESIAN_POINT('',(-112.408471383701,-3.28314601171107,19.729842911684));
#414=CARTESIAN_POINT('',(-112.500240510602,-3.06778359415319,19.7645596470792));
#415=CARTESIAN_POINT('',(-112.665018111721,-2.62913934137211,19.8276753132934));
#416=CARTESIAN_POINT('',(-112.738030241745,-2.40585905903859,19.8560754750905));
#417=CARTESIAN_POINT('',(-112.864528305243,-1.95305901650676,19.9057131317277));
#418=CARTESIAN_POINT('',(-112.918015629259,-1.72353970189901,19.926951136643));
#419=CARTESIAN_POINT('',(-113.002224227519,-1.27415358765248,19.9605660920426));
#420=CARTESIAN_POINT('',(-113.034125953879,-1.05454166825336,19.9734009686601));
#421=CARTESIAN_POINT('',(-113.079807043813,-0.613140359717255,19.9918193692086));
#422=CARTESIAN_POINT('',(-113.093587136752,-0.391351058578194,19.9974031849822));
#423=CARTESIAN_POINT('',(-113.102871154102,0.0526198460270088,20.0011625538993));
#424=CARTESIAN_POINT('',(-113.098379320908,0.27480134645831,19.9993398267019));
#425=CARTESIAN_POINT('',(-113.071179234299,0.717859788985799,19.9883410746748));
#426=CARTESIAN_POINT('',(-113.048471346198,0.938736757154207,19.9791651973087));
#427=CARTESIAN_POINT('',(-112.986569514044,1.36724903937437,19.954311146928));
#428=CARTESIAN_POINT('',(-112.948192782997,1.5750219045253,19.9389557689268));
#429=CARTESIAN_POINT('',(-112.855464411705,1.98649733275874,19.9021734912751));
#430=CARTESIAN_POINT('',(-112.801107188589,2.19019844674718,19.8807444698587));
#431=CARTESIAN_POINT('',(-112.676934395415,2.59208434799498,19.8323487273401));
#432=CARTESIAN_POINT('',(-112.607123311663,2.79027071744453,19.8053836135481));
#433=CARTESIAN_POINT('',(-112.452592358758,3.18006963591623,19.7465447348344));
#434=CARTESIAN_POINT('',(-112.367866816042,3.371679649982,19.7146691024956));
#435=CARTESIAN_POINT('',(-112.181383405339,3.75288057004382,19.6457256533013));
#436=CARTESIAN_POINT('',(-112.079186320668,3.94223332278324,19.6085295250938));
#437=CARTESIAN_POINT('',(-111.860392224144,4.31174450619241,19.5306049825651));
#438=CARTESIAN_POINT('',(-111.743790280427,4.49189975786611,19.4898753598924));
#439=CARTESIAN_POINT('',(-111.496967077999,4.84203534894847,19.4058526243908));
#440=CARTESIAN_POINT('',(-111.366743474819,5.01201392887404,19.3625590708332));
#441=CARTESIAN_POINT('',(-111.093473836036,5.34090761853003,19.2744311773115));
#442=CARTESIAN_POINT('',(-110.95042722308,5.49982222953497,19.2295967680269));
#443=CARTESIAN_POINT('',(-110.642171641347,5.81617801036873,19.1363810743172));
#444=CARTESIAN_POINT('',(-110.476117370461,5.97278662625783,19.0879656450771));
#445=CARTESIAN_POINT('',(-110.131317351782,6.27149075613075,18.9919197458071));
#446=CARTESIAN_POINT('',(-109.952575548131,6.41359074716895,18.9442890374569));
#447=CARTESIAN_POINT('',(-109.583258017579,6.68251089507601,18.8511091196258));
#448=CARTESIAN_POINT('',(-109.39267539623,6.80932202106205,18.8055611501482));
#449=CARTESIAN_POINT('',(-109.000949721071,7.04661740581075,18.7179373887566));
#450=CARTESIAN_POINT('',(-108.79981115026,7.15710852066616,18.6758601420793));
#451=CARTESIAN_POINT('',(-108.385735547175,7.36211754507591,18.5960069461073));
#452=CARTESIAN_POINT('',(-108.172689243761,7.4564366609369,18.5582861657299));
#453=CARTESIAN_POINT('',(-107.738475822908,7.62660439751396,18.4890062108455));
#454=CARTESIAN_POINT('',(-107.517312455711,7.70246142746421,18.4574442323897));
#455=CARTESIAN_POINT('',(-107.06848440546,7.83492790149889,18.4016053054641));
#456=CARTESIAN_POINT('',(-106.840822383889,7.89154510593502,18.3773254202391));
#457=CARTESIAN_POINT('',(-106.380747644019,7.98489928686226,18.3369567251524));
#458=CARTESIAN_POINT('',(-106.148335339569,8.02163798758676,18.3208672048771));
#459=CARTESIAN_POINT('',(-105.69796213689,8.07281706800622,18.2983698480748));
#460=CARTESIAN_POINT('',(-105.480195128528,8.08869834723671,18.2913371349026));
#461=CARTESIAN_POINT('',(-105.043982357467,8.10281912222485,18.2850864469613));
#462=CARTESIAN_POINT('',(-104.825536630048,8.10105952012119,18.2858680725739));
#463=CARTESIAN_POINT('',(-104.389698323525,8.07992140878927,18.2952179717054));
#464=CARTESIAN_POINT('',(-104.172305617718,8.06054507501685,18.3037852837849));
#465=CARTESIAN_POINT('',(-103.740212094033,8.00439867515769,18.3284079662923));
#466=CARTESIAN_POINT('',(-103.525511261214,7.96762870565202,18.3444632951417));
#467=CARTESIAN_POINT('',(-103.109281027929,7.87899425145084,18.3827003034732));
#468=CARTESIAN_POINT('',(-102.907576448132,7.82782592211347,18.4045974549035));
#469=CARTESIAN_POINT('',(-102.509277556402,7.71034555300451,18.4541223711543));
#470=CARTESIAN_POINT('',(-102.312685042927,7.64402826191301,18.4817521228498));
#471=CARTESIAN_POINT('',(-101.925853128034,7.49682896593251,18.5419489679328));
#472=CARTESIAN_POINT('',(-101.735612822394,7.41594904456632,18.5745153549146));
#473=CARTESIAN_POINT('',(-101.362404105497,7.24019743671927,18.6437243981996));
#474=CARTESIAN_POINT('',(-101.179438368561,7.14532066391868,18.6803685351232));
#475=CARTESIAN_POINT('',(-100.811381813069,6.93634048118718,18.7590072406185));
#476=CARTESIAN_POINT('',(-100.626782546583,6.8214413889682,18.8011888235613));
#477=CARTESIAN_POINT('',(-100.26777997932,6.57747679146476,18.8879208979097));
#478=CARTESIAN_POINT('',(-100.093377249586,6.44841049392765,18.932471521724));
#479=CARTESIAN_POINT('',(-99.7555968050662,6.17682899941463,19.0228091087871));
#480=CARTESIAN_POINT('',(-99.5922237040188,6.03430823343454,19.0685965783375));
#481=CARTESIAN_POINT('',(-99.2774813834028,5.73669576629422,19.1602337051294));
#482=CARTESIAN_POINT('',(-99.126108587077,5.58160783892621,19.2060833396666));
#483=CARTESIAN_POINT('',(-98.8263194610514,5.24873029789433,19.2998110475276));
#484=CARTESIAN_POINT('',(-98.6787958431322,5.07011468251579,19.347616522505));
#485=CARTESIAN_POINT('',(-98.3993545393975,4.70054560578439,19.4407090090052));
#486=CARTESIAN_POINT('',(-98.2674316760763,4.5095962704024,19.4859968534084));
#487=CARTESIAN_POINT('',(-98.0200294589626,4.11631109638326,19.5728526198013));
#488=CARTESIAN_POINT('',(-97.9045622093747,3.91396702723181,19.6144177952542));
#489=CARTESIAN_POINT('',(-97.6911665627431,3.49932983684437,19.6926175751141));
#490=CARTESIAN_POINT('',(-97.5932367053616,3.28703754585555,19.7292525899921));
#491=CARTESIAN_POINT('',(-97.4174184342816,2.85784311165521,19.7959350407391));
#492=CARTESIAN_POINT('',(-97.3392019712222,2.6410920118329,19.8260888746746));
#493=CARTESIAN_POINT('',(-97.2013523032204,2.20096724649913,19.8797603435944));
#494=CARTESIAN_POINT('',(-97.1417172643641,1.9775942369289,19.9032786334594));
#495=CARTESIAN_POINT('',(-97.0418076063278,1.52656255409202,19.9429368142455));
#496=CARTESIAN_POINT('',(-97.0014810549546,1.29891710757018,19.959096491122));
#497=CARTESIAN_POINT('',(-96.94043734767,0.840712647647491,19.9836373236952));
#498=CARTESIAN_POINT('',(-96.9197054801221,0.610155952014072,19.9920243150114));
#499=CARTESIAN_POINT('',(-96.9059195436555,0.316014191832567,19.9976033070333));
#500=CARTESIAN_POINT('',(-96.9037002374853,0.252837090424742,19.998501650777));
#501=CARTESIAN_POINT('',(-96.9007402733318,0.126442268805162,19.9997001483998));
#502=CARTESIAN_POINT('',(-96.8999996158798,0.0632245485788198,20.0000003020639));
#503=CARTESIAN_POINT('',(-96.9,0.,20.));
#504=B_SPLINE_CURVE_WITH_KNOTS('',3,(#346,#347,#348,#349,#350,#351,#352,#353,#354,#355,#356,
#357,#358,#359,#360,#361,#362,#363,#364,#365,#366,#367,#368,#369,#370,#371,#372,#373,#374,#375,
#376,#377,#378,#379,#380,#381,#382,#383,#384,#385,#386,#387,#388,#389,#390,#391,#392,#393,#394,
#395,#396,#397,#398,#399,#400,#401,#402,#403,#404,#405,#406,#407,#408,#409,#410,#411,#412,#413,
#414,#415,#416,#417,#418,#419,#420,#421,#422,#423,#424,#425,#426,#427,#428,#429,#430,#431,#432,
#433,#434,#435,#436,#437,#438,#439,#440,#441,#442,#443,#444,#445,#446,#447,#448,#449,#450,#451,
#452,#453,#454,#455,#456,#457,#458,#459,#460,#461,#462,#463,#464,#465,#466,#467,#468,#469,#470,
#471,#472,#473,#474,#475,#476,#477,#478,#479,#480,#481,#482,#483,#484,#485,#486,#487,#488,#489,
#490,#491,#492,#493,#494,#495,#496,#497,#498,#499,#500,#501,#502,#503),.UNSPECIFIED.,.T.,.F.,(4,
2,2,2,2,2,2,2,2,2,2,2,2,2,2,2,2,2,2,2,2,2,2,2,2,2,2,2,2,2,2,2,2,2,2,2,2,2,2,2,2,2,2,2,2,2,2,2,2,
2,2,2,2,2,2,2,2,2,2,2,2,2,2,2,2,2,2,2,2,2,2,2,2,2,2,2,2,2,4),(0.,0.652596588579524,
1.30562240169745,1.9601462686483,2.61471503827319,3.26705291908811,3.91941523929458,
4.57139167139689,5.22360494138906,5.90428093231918,6.58498080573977,7.26612153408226,
7.94703551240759,8.6595465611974,9.37176332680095,10.0838677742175,10.7959224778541,
11.4750993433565,12.1542562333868,12.8331158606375,13.5119426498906,14.1419204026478,
14.7721156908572,15.402156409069,16.0324398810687,16.6755035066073,17.3187851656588,
17.9621556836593,18.6055602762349,19.3002237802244,19.9946836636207,20.6895501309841,
21.3841380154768,22.0934810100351,22.8025187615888,23.5114182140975,24.2202671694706,
24.8862793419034,25.5522647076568,26.2180954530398,26.8839128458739,27.5187156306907,
28.1537404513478,28.788581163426,29.4236638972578,30.0780389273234,30.7326386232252,
31.3873511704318,32.0420932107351,32.7412878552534,33.440266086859,34.139655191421,
34.8387496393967,35.5459021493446,36.2527319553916,36.9592763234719,37.6657593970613,
38.3202973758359,38.974801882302,39.6292255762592,40.283645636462,40.9106764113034,
41.5379248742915,42.1650836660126,42.7924709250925,43.4562239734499,44.1200141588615,
44.7840803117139,45.44794778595,46.1567243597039,46.8652650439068,47.5743242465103,
48.2833243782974,48.9796040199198,49.67581491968,50.37014261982,51.0639486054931,
51.2536033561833,51.4432581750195),.UNSPECIFIED.);
#505=CARTESIAN_POINT('',(-96.9,0.,20.));
#506=VERTEX_POINT('',#505);
#507=EDGE_CURVE('E46',#506,#506,#504,.T.);
#508=ORIENTED_EDGE('',*,*,#507,.T.);
#509=EDGE_LOOP('',(#508));
#510=FACE_BOUND('',#509,.T.);
#511=CARTESIAN_POINT('',(120.,1.07552855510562E-13,0.));
#512=DIRECTION('',(-1.,0.,0.));
#513=DIRECTION('',(0.,0.,1.));
#514=AXIS2_PLACEMENT_3D('',#511,#512,#513);
#515=CIRCLE('',#514,20.);
#516=CARTESIAN_POINT('',(120.,1.07552855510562E-13,20.));
#517=VERTEX_POINT('',#516);
#518=EDGE_CURVE('E81',#517,#517,#515,.T.);
#519=ORIENTED_EDGE('',*,*,#518,.T.);
#520=EDGE_LOOP('',(#519));
#521=FACE_BOUND('',#520,.T.);
#522=CARTESIAN_POINT('',(-120.,-1.66533453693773E-13,0.));
#523=DIRECTION('',(1.,0.,0.));
#524=DIRECTION('',(0.,0.,-1.));
#525=AXIS2_PLACEMENT_3D('',#522,#523,#524);
#526=CIRCLE('',#525,20.);
#527=CARTESIAN_POINT('',(-120.,-1.66533453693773E-13,-20.));
#528=VERTEX_POINT('',#527);
#529=EDGE_CURVE('E84',#528,#528,#526,.T.);
#530=ORIENTED_EDGE('',*,*,#529,.T.);
#531=EDGE_LOOP('',(#530));
#532=FACE_BOUND('',#531,.T.);
#533=CARTESIAN_POINT('',(87.,17.3205080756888,-10.));
#534=CARTESIAN_POINT('',(86.7393369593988,17.3205095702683,-9.99999887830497));
#535=CARTESIAN_POINT('',(86.4786512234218,17.3264124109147,-9.98979463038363));
#536=CARTESIAN_POINT('',(85.9592885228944,17.3498046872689,-9.94911125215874));
#537=CARTESIAN_POINT('',(85.7006125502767,17.3672995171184,-9.91862268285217));
#538=CARTESIAN_POINT('',(85.1869766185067,17.4132568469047,-9.83771551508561));
#539=CARTESIAN_POINT('',(84.93202314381,17.4417365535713,-9.78726564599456));
#540=CARTESIAN_POINT('',(84.4279501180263,17.5086546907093,-9.66704369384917));
#541=CARTESIAN_POINT('',(84.1788331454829,17.5470974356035,-9.59726323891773));
#542=CARTESIAN_POINT('',(83.689526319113,17.6323996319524,-9.43962165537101));
#543=CARTESIAN_POINT('',(83.4492931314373,17.6792090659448,-9.3518675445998));
#544=CARTESIAN_POINT('',(82.9774457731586,17.779982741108,-9.15882440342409));
#545=CARTESIAN_POINT('',(82.7458347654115,17.8339495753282,-9.05352901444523));
#546=CARTESIAN_POINT('',(82.2924546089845,17.9475017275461,-8.82628481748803));
#547=CARTESIAN_POINT('',(82.0706831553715,18.007085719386,-8.70433993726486));
#548=CARTESIAN_POINT('',(81.6378403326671,18.1303531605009,-8.44458163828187));
#549=CARTESIAN_POINT('',(81.426769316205,18.1940367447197,-8.30676769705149));
#550=CARTESIAN_POINT('',(80.9991624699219,18.3293639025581,-8.00400718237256));
#551=CARTESIAN_POINT('',(80.7836175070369,18.401230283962,-7.83775940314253));
#552=CARTESIAN_POINT('',(80.3670650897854,18.5460965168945,-7.48852658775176));
#553=CARTESIAN_POINT('',(80.1660539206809,18.619096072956,-7.30554585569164));
#554=CARTESIAN_POINT('',(79.7793054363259,18.7644955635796,-6.92354675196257));
#555=CARTESIAN_POINT('',(79.5935807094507,18.8368949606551,-6.72451542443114));
#556=CARTESIAN_POINT('',(79.2386532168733,18.9792540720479,-6.31154503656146));
#557=CARTESIAN_POINT('',(79.0694446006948,19.0492146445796,-6.09761130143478));
#558=CARTESIAN_POINT('',(78.7376358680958,19.1896470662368,-5.64077435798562));
#559=CARTESIAN_POINT('',(78.5762607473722,19.2598322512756,-5.39689043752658));
#560=CARTESIAN_POINT('',(78.2747934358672,19.3935808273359,-4.89454568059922));
#561=CARTESIAN_POINT('',(78.1347024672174,19.4571438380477,-4.63608400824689));
#562=CARTESIAN_POINT('',(77.8772510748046,19.5757886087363,-4.10635184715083));
#563=CARTESIAN_POINT('',(77.759879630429,19.6308744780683,-3.83508764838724));
#564=CARTESIAN_POINT('',(77.5491370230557,19.7309453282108,-3.28159286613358));
#565=CARTESIAN_POINT('',(77.4557633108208,19.775931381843,-2.99936345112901));
#566=CARTESIAN_POINT('',(77.2999712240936,19.8516061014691,-2.44661617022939));
#567=CARTESIAN_POINT('',(77.2358232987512,19.8830841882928,-2.1766933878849));
#568=CARTESIAN_POINT('',(77.1300693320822,19.9352303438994,-1.63143316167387));
#569=CARTESIAN_POINT('',(77.0884623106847,19.9558988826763,-1.35609595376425));
#570=CARTESIAN_POINT('',(77.0283601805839,19.9858180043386,-0.802434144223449));
#571=CARTESIAN_POINT('',(77.0098532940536,19.9950744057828,-0.524111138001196));
#572=CARTESIAN_POINT('',(76.996171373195,20.0019136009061,0.0332441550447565));
#573=CARTESIAN_POINT('',(77.0009949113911,19.9994971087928,0.312276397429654));
#574=CARTESIAN_POINT('',(77.0324639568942,19.9837839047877,0.844365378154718));
#575=CARTESIAN_POINT('',(77.0571725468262,19.9714530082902,1.09756809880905));
#576=CARTESIAN_POINT('',(77.1256826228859,19.9374335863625,1.60072224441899));
#577=CARTESIAN_POINT('',(77.1694827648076,19.9157457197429,1.8506738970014));
#578=CARTESIAN_POINT('',(77.275699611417,19.8635314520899,2.34564683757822));
#579=CARTESIAN_POINT('',(77.3381169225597,19.8330047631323,2.59066796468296));
#580=CARTESIAN_POINT('',(77.4809309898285,19.7638249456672,3.0742307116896));
#581=CARTESIAN_POINT('',(77.5613283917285,19.7251715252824,3.31277209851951));
#582=CARTESIAN_POINT('',(77.7405720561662,19.6400278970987,3.78519130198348));
#583=CARTESIAN_POINT('',(77.8396540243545,19.5934383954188,4.01896179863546));
#584=CARTESIAN_POINT('',(78.0546901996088,19.4938328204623,4.47722728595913));
#585=CARTESIAN_POINT('',(78.1706503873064,19.4408144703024,4.70171895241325));
#586=CARTESIAN_POINT('',(78.5425147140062,19.2738101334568,5.35951935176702));
#587=CARTESIAN_POINT('',(78.82251161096,19.1518214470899,5.77743819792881));
#588=CARTESIAN_POINT('',(79.4690400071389,18.8844067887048,6.60185513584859));
#589=CARTESIAN_POINT('',(79.8412495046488,18.7378553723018,7.00353936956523));
#590=CARTESIAN_POINT('',(80.4446384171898,18.5185765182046,7.55658054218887));
#591=CARTESIAN_POINT('',(80.6534519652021,18.4455210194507,7.73279224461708));
#592=CARTESIAN_POINT('',(81.0853226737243,18.301419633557,8.0679151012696));
#593=CARTESIAN_POINT('',(81.3083819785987,18.2303740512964,8.22682364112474));
#594=CARTESIAN_POINT('',(81.7823337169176,18.0878347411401,8.53586780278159));
#595=CARTESIAN_POINT('',(82.0340939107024,18.0166021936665,8.6847949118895));
#596=CARTESIAN_POINT('',(82.551050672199,17.8810231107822,8.96061518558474));
#597=CARTESIAN_POINT('',(82.8162411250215,17.8166734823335,9.0875182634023));
#598=CARTESIAN_POINT('',(83.35840289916,17.6972138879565,9.31801905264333));
#599=CARTESIAN_POINT('',(83.6353671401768,17.6420984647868,9.4216305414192));
#600=CARTESIAN_POINT('',(84.1992437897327,17.5432965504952,9.60435110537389));
#601=CARTESIAN_POINT('',(84.4861548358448,17.4996085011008,9.68346352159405));
#602=CARTESIAN_POINT('',(85.0445047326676,17.4285246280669,9.81078056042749));
#603=CARTESIAN_POINT('',(85.3153693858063,17.400112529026,9.86093677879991));
#604=CARTESIAN_POINT('',(85.8613257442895,17.355765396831,9.93878416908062));
#605=CARTESIAN_POINT('',(86.1364172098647,17.3398296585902,9.96647661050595));
#606=CARTESIAN_POINT('',(86.6882306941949,17.3211203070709,9.99895720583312));
#607=CARTESIAN_POINT('',(86.964951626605,17.3183387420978,10.0037591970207));
#608=CARTESIAN_POINT('',(87.5176428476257,17.3260388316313,9.99041751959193));
#609=CARTESIAN_POINT('',(87.7936131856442,17.3365195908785,9.97227539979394));
#610=CARTESIAN_POINT('',(88.3121699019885,17.3684286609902,9.91658048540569));
#611=CARTESIAN_POINT('',(88.5550956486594,17.3885290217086,9.88137691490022));
#612=CARTESIAN_POINT('',(89.0368418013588,17.4382137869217,9.7934289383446));
#613=CARTESIAN_POINT('',(89.2756608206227,17.467801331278,9.7406787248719));
#614=CARTESIAN_POINT('',(89.7476271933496,17.5355331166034,9.61821012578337));
#615=CARTESIAN_POINT('',(89.9807752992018,17.5736762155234,9.54849400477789));
#616=CARTESIAN_POINT('',(90.4402243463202,17.6574071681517,9.39275103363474));
#617=CARTESIAN_POINT('',(90.6665225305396,17.7029979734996,9.30671771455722));
#618=CARTESIAN_POINT('',(91.3538380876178,17.8535843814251,9.01657018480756));
#619=CARTESIAN_POINT('',(91.80167280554,17.9691397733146,8.78600743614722));
#620=CARTESIAN_POINT('',(92.6548101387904,18.2156365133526,8.26280380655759));
#621=CARTESIAN_POINT('',(93.06009074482,18.3465857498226,7.97013103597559));
#622=CARTESIAN_POINT('',(93.6554100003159,18.5540860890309,7.4688840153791));
#623=CARTESIAN_POINT('',(93.862193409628,18.6294365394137,7.27935116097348));
#624=CARTESIAN_POINT('',(94.2592423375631,18.7793184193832,6.88345408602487));
#625=CARTESIAN_POINT('',(94.4495127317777,18.8538500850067,6.67709486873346));
#626=CARTESIAN_POINT('',(94.8125944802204,19.0002370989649,6.2483870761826));
#627=CARTESIAN_POINT('',(94.9853926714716,19.0720904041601,6.02602665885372));
#628=CARTESIAN_POINT('',(95.3121500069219,19.2111944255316,5.5666478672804));
#629=CARTESIAN_POINT('',(95.4661171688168,19.2784470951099,5.32963579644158));
#630=CARTESIAN_POINT('',(95.7579356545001,19.4083463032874,4.83560208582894));
#631=CARTESIAN_POINT('',(95.8952456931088,19.4708214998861,4.57821478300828));
#632=CARTESIAN_POINT('',(96.147470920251,19.587335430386,4.05082787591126));
#633=CARTESIAN_POINT('',(96.262385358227,19.6413738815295,3.78082784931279));
#634=CARTESIAN_POINT('',(96.4684323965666,19.7393769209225,3.23033940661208));
#635=CARTESIAN_POINT('',(96.5595819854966,19.7833487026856,2.94985864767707));
#636=CARTESIAN_POINT('',(96.7170190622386,19.8599022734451,2.38049331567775));
#637=CARTESIAN_POINT('',(96.7833094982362,19.8924854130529,2.0916097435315));
#638=CARTESIAN_POINT('',(96.8851895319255,19.9427983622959,1.5348050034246));
#639=CARTESIAN_POINT('',(96.9230386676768,19.9616170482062,1.26739371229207));
#640=CARTESIAN_POINT('',(96.9769866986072,19.9884894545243,0.729851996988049));
#641=CARTESIAN_POINT('',(96.9930869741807,19.9965438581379,0.459721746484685));
#642=CARTESIAN_POINT('',(97.0033264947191,20.0016629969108,-0.0809759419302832));
#643=CARTESIAN_POINT('',(96.9974722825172,19.998731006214,-0.351543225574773));
#644=CARTESIAN_POINT('',(96.9638943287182,19.9819662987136,-0.890971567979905));
#645=CARTESIAN_POINT('',(96.9361711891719,19.9681338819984,-1.15983267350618));
#646=CARTESIAN_POINT('',(96.8617599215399,19.9312153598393,-1.67605139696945));
#647=CARTESIAN_POINT('',(96.81644464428,19.9088004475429,-1.9236568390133));
#648=CARTESIAN_POINT('',(96.707542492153,19.8553300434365,-2.41384547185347));
#649=CARTESIAN_POINT('',(96.6439566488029,19.8242750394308,-2.6564289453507));
#650=CARTESIAN_POINT('',(96.4991522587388,19.7542370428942,-3.1350632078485));
#651=CARTESIAN_POINT('',(96.4179353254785,19.7152547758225,-3.37111459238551));
#652=CARTESIAN_POINT('',(96.2385691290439,19.6302044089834,-3.83546861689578));
#653=CARTESIAN_POINT('',(96.1404133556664,19.5841335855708,-4.06376823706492));
#654=CARTESIAN_POINT('',(95.9234816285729,19.483810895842,-4.52085803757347));
#655=CARTESIAN_POINT('',(95.8040081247,19.4292950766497,-4.74925902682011));
#656=CARTESIAN_POINT('',(95.5484340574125,19.3148302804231,-5.19522438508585));
#657=CARTESIAN_POINT('',(95.412327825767,19.2548794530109,-5.41278502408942));
#658=CARTESIAN_POINT('',(95.1244032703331,19.1308402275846,-5.83606045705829));
#659=CARTESIAN_POINT('',(94.9725818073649,19.0667510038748,-6.04177287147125));
#660=CARTESIAN_POINT('',(94.6541249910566,18.9358010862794,-6.44045588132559));
#661=CARTESIAN_POINT('',(94.4874888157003,18.8689402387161,-6.63342576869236));
#662=CARTESIAN_POINT('',(94.1229047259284,18.7271146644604,-7.02443076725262));
#663=CARTESIAN_POINT('',(93.9234915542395,18.6520069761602,-7.22105023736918));
#664=CARTESIAN_POINT('',(93.5088897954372,18.5021161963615,-7.59688252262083));
#665=CARTESIAN_POINT('',(93.2937056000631,18.4273330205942,-7.77610015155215));
#666=CARTESIAN_POINT('',(92.8483328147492,18.2800108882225,-8.11637930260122));
#667=CARTESIAN_POINT('',(92.6181294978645,18.2074742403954,-8.27742256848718));
#668=CARTESIAN_POINT('',(92.1439787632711,18.0668000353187,-8.58012843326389));
#669=CARTESIAN_POINT('',(91.9000294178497,17.9986630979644,-8.72178830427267));
#670=CARTESIAN_POINT('',(91.3916255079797,17.8668466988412,-8.9888082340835));
#671=CARTESIAN_POINT('',(91.1267646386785,17.8033795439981,-9.1135019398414));
#672=CARTESIAN_POINT('',(90.5854716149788,17.6857538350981,-9.3397203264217));
#673=CARTESIAN_POINT('',(90.3090455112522,17.6315904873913,-9.44125694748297));
#674=CARTESIAN_POINT('',(89.7471888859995,17.5348420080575,-9.61975104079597));
#675=CARTESIAN_POINT('',(89.4617836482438,17.4922271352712,-9.69677174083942));
#676=CARTESIAN_POINT('',(88.8838144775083,17.4202953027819,-9.82541504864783));
#677=CARTESIAN_POINT('',(88.5912557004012,17.3909690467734,-9.8770554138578));
#678=CARTESIAN_POINT('',(88.082004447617,17.3529508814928,-9.94364603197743));
#679=CARTESIAN_POINT('',(87.8663516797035,17.3408143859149,-9.96475859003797));
#680=CARTESIAN_POINT('',(87.4338045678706,17.3245920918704,-9.99293651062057));
#681=CARTESIAN_POINT('',(87.2169101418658,17.3205068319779,-10.0000009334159));
#682=CARTESIAN_POINT('',(87.,17.3205080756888,-10.));
#683=B_SPLINE_CURVE_WITH_KNOTS('',3,(#533,#534,#535,#536,#537,#538,#539,#540,#541,#542,#543,
#544,#545,#546,#547,#548,#549,#550,#551,#552,#553,#554,#555,#556,#557,#558,#559,#560,#561,#562,
#563,#564,#565,#566,#567,#568,#569,#570,#571,#572,#573,#574,#575,#576,#577,#578,#579,#580,#581,
#582,#583,#584,#585,#586,#587,#588,#589,#590,#591,#592,#593,#594,#595,#596,#597,#598,#599,#600,
#601,#602,#603,#604,#605,#606,#607,#608,#609,#610,#611,#612,#613,#614,#615,#616,#617,#618,#619,
#620,#621,#622,#623,#624,#625,#626,#627,#628,#629,#630,#631,#632,#633,#634,#635,#636,#637,#638,
#639,#640,#641,#642,#643,#644,#645,#646,#647,#648,#649,#650,#651,#652,#653,#654,#655,#656,#657,
#658,#659,#660,#661,#662,#663,#664,#665,#666,#667,#668,#669,#670,#671,#672,#673,#674,#675,#676,
#677,#678,#679,#680,#681,#682),.UNSPECIFIED.,.T.,.F.,(4,2,2,2,2,2,2,2,2,2,2,2,2,2,2,2,2,2,2,2,2,
2,2,2,2,2,2,2,2,2,2,2,2,2,2,2,2,2,2,2,2,2,2,2,2,2,2,2,2,2,2,2,2,2,2,2,2,2,2,2,2,2,2,2,2,2,2,2,2,
2,2,2,2,2,4),(0.,0.781764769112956,1.56389357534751,2.34725251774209,3.13095125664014,
3.9101127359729,4.68955727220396,5.4688182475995,6.24810488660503,7.09181817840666,
7.93531505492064,8.77949974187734,9.62338430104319,10.5244589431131,11.4255853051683,
12.326273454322,13.2268658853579,14.063393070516,14.8998838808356,15.7359480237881,
16.571961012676,17.3351709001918,18.0983270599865,18.8615080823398,19.6247165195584,
20.3982891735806,21.1721366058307,22.7189130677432,24.411902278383,25.2596540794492,
26.1075337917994,27.0095657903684,27.9111907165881,28.8122809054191,29.713248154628,
30.542861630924,31.3724282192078,32.2014932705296,33.0305023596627,33.7685142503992,
34.5067706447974,35.244928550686,35.9833797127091,37.5272041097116,39.0718230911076,
39.9423348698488,40.8125887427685,41.6834934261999,42.5540260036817,43.4478458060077,
44.3416955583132,45.2349045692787,46.1280076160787,46.9391312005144,47.7502033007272,
48.5610337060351,49.3718417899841,50.1291222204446,50.8863599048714,51.6435283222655,
52.400988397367,53.190547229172,53.980375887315,54.7703626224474,55.560393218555,
56.4292490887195,57.2978639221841,58.1673436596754,59.0369456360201,59.9343645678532,
60.8313197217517,61.7259424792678,62.6199384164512,63.2704386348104,63.9209823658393),.UNSPECIFIED.);
#684=CARTESIAN_POINT('',(87.,17.3205080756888,-10.));
#685=VERTEX_POINT('',#684);
#686=EDGE_CURVE('E10',#685,#685,#683,.T.);
#687=ORIENTED_EDGE('',*,*,#686,.F.);
#688=EDGE_LOOP('',(#687));
#689=FACE_BOUND('',#688,.T.);
#690=ADVANCED_FACE('F28',(#180,#345,#510,#521,#532,#689),#23,.T.);
#691=CARTESIAN_POINT('',(-122.,0.,0.));
#692=DIRECTION('',(1.,0.,0.));
#693=DIRECTION('',(0.,0.,-1.));
#694=AXIS2_PLACEMENT_3D('',#691,#692,#693);
#695=PLANE('',#694);
#696=CARTESIAN_POINT('',(-122.,0.,0.));
#697=DIRECTION('',(1.,0.,0.));
#698=DIRECTION('',(0.,0.,-1.));
#699=AXIS2_PLACEMENT_3D('',#696,#697,#698);
#700=CIRCLE('',#699,18.);
#701=CARTESIAN_POINT('',(-122.,0.,-18.));
#702=VERTEX_POINT('',#701);
#703=EDGE_CURVE('E75',#702,#702,#700,.F.);
#704=ORIENTED_EDGE('',*,*,#703,.T.);
#705=EDGE_LOOP('',(#704));
#706=FACE_BOUND('',#705,.T.);
#707=ADVANCED_FACE('F30',(#706),#695,.F.);
#708=CARTESIAN_POINT('',(122.,20.,0.));
#709=DIRECTION('',(-1.,0.,0.));
#710=DIRECTION('',(0.,0.,1.));
#711=AXIS2_PLACEMENT_3D('',#708,#709,#710);
#712=PLANE('',#711);
#713=CARTESIAN_POINT('',(122.,1.11022302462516E-13,0.));
#714=DIRECTION('',(-1.,0.,0.));
#715=DIRECTION('',(0.,0.,1.));
#716=AXIS2_PLACEMENT_3D('',#713,#714,#715);
#717=CIRCLE('',#716,18.);
#718=CARTESIAN_POINT('',(122.,1.11022302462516E-13,18.));
#719=VERTEX_POINT('',#718);
#720=EDGE_CURVE('E78',#719,#719,#717,.F.);
#721=ORIENTED_EDGE('',*,*,#720,.T.);
#722=EDGE_LOOP('',(#721));
#723=FACE_BOUND('',#722,.T.);
#724=ADVANCED_FACE('F110',(#723),#712,.F.);
#725=CARTESIAN_POINT('',(120.,1.07552855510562E-13,0.));
#726=DIRECTION('',(-1.,0.,0.));
#727=DIRECTION('',(0.,0.,1.));
#728=AXIS2_PLACEMENT_3D('',#725,#726,#727);
#729=CONICAL_SURFACE('',#728,20.,0.785398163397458);
#730=ORIENTED_EDGE('',*,*,#720,.F.);
#731=EDGE_LOOP('',(#730));
#732=FACE_BOUND('',#731,.T.);
#733=ORIENTED_EDGE('',*,*,#518,.F.);
#734=EDGE_LOOP('',(#733));
#735=FACE_BOUND('',#734,.T.);
#736=ADVANCED_FACE('F124',(#732,#735),#729,.T.);
#737=CARTESIAN_POINT('',(-122.,0.,0.));
#738=DIRECTION('',(1.,0.,0.));
#739=DIRECTION('',(0.,0.,-1.));
#740=AXIS2_PLACEMENT_3D('',#737,#738,#739);
#741=CONICAL_SURFACE('',#740,18.,0.785398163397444);
#742=ORIENTED_EDGE('',*,*,#529,.F.);
#743=EDGE_LOOP('',(#742));
#744=FACE_BOUND('',#743,.T.);
#745=ORIENTED_EDGE('',*,*,#703,.F.);
#746=EDGE_LOOP('',(#745));
#747=FACE_BOUND('',#746,.T.);
#748=ADVANCED_FACE('F67',(#744,#747),#741,.T.);
#749=CARTESIAN_POINT('',(-105.,0.,-20.));
#750=DIRECTION('',(0.,0.,1.));
#751=DIRECTION('',(1.,0.,0.));
#752=AXIS2_PLACEMENT_3D('',#749,#750,#751);
#753=CYLINDRICAL_SURFACE('',#752,8.10000000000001);
#754=ORIENTED_EDGE('',*,*,#507,.F.);
#755=EDGE_LOOP('',(#754));
#756=FACE_BOUND('',#755,.T.);
#757=ORIENTED_EDGE('',*,*,#342,.F.);
#758=EDGE_LOOP('',(#757));
#759=FACE_BOUND('',#758,.T.);
#760=ADVANCED_FACE('F62',(#756,#759),#753,.F.);
#761=CARTESIAN_POINT('',(-75.,33.0000000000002,0.));
#762=DIRECTION('',(0.,-1.,0.));
#763=DIRECTION('',(0.,0.,-1.));
#764=AXIS2_PLACEMENT_3D('',#761,#762,#763);
#765=CYLINDRICAL_SURFACE('',#764,10.);
#766=CARTESIAN_POINT('',(-75.,33.0000000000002,0.));
#767=DIRECTION('',(0.,1.,0.));
#768=DIRECTION('',(0.,0.,1.));
#769=AXIS2_PLACEMENT_3D('',#766,#767,#768);
#770=CIRCLE('',#769,10.);
#771=CARTESIAN_POINT('',(-75.,33.0000000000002,10.));
#772=VERTEX_POINT('',#771);
#773=EDGE_CURVE('E87',#772,#772,#770,.T.);
#774=ORIENTED_EDGE('',*,*,#773,.F.);
#775=EDGE_LOOP('',(#774));
#776=FACE_BOUND('',#775,.T.);
#777=ORIENTED_EDGE('',*,*,#177,.T.);
#778=EDGE_LOOP('',(#777));
#779=FACE_BOUND('',#778,.T.);
#780=ADVANCED_FACE('F57',(#776,#779),#765,.T.);
#781=CARTESIAN_POINT('',(-75.,33.0000000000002,0.));
#782=DIRECTION('',(0.,1.,0.));
#783=DIRECTION('',(0.,0.,1.));
#784=AXIS2_PLACEMENT_3D('',#781,#782,#783);
#785=PLANE('',#784);
#786=ORIENTED_EDGE('',*,*,#773,.T.);
#787=EDGE_LOOP('',(#786));
#788=FACE_BOUND('',#787,.T.);
#789=ADVANCED_FACE('F61',(#788),#785,.T.);
#790=CARTESIAN_POINT('',(87.,33.,0.));
#791=DIRECTION('',(0.,-1.,0.));
#792=DIRECTION('',(0.,0.,-1.));
#793=AXIS2_PLACEMENT_3D('',#790,#791,#792);
#794=CYLINDRICAL_SURFACE('',#793,10.);
#795=CARTESIAN_POINT('',(87.,33.,0.));
#796=DIRECTION('',(0.,1.,0.));
#797=DIRECTION('',(0.,0.,1.));
#798=AXIS2_PLACEMENT_3D('',#795,#796,#797);
#799=CIRCLE('',#798,10.);
#800=CARTESIAN_POINT('',(87.,33.,10.));
#801=VERTEX_POINT('',#800);
#802=EDGE_CURVE('E90',#801,#801,#799,.T.);
#803=ORIENTED_EDGE('',*,*,#802,.F.);
#804=EDGE_LOOP('',(#803));
#805=FACE_BOUND('',#804,.T.);
#806=ORIENTED_EDGE('',*,*,#686,.T.);
#807=EDGE_LOOP('',(#806));
#808=FACE_BOUND('',#807,.T.);
#809=ADVANCED_FACE('F96',(#805,#808),#794,.T.);
#810=CARTESIAN_POINT('',(87.,33.,0.));
#811=DIRECTION('',(0.,1.,0.));
#812=DIRECTION('',(0.,0.,1.));
#813=AXIS2_PLACEMENT_3D('',#810,#811,#812);
#814=PLANE('',#813);
#815=ORIENTED_EDGE('',*,*,#802,.T.);
#816=EDGE_LOOP('',(#815));
#817=FACE_BOUND('',#816,.T.);
#818=ADVANCED_FACE('F94',(#817),#814,.T.);
#819=CLOSED_SHELL('',(#690,#707,#724,#736,#748,#760,#780,#789,#809,#818));
#820=MANIFOLD_SOLID_BREP('B2',#819);
#821=ADVANCED_BREP_SHAPE_REPRESENTATION('',(#18,#820),#14);
#822=SHAPE_DEFINITION_REPRESENTATION(#9,#821);
ENDSEC;
END-ISO-10303-21;
